VERSION 5.7 ;
  NOWIREEXTENSIONATPIN ON ;
  DIVIDERCHAR "/" ;
  BUSBITCHARS "[]" ;
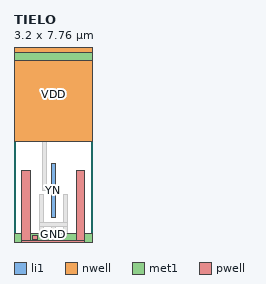
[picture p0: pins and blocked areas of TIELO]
MACRO TIELO
  CLASS CORE WELLTAP ;
  FOREIGN TIELO ;
  ORIGIN 0.000 0.000 ;
  SIZE 3.200 BY 7.760 ;
  SYMMETRY X Y ;
  SITE unitrh ;
  PIN YN
    DIRECTION OUTPUT ;
    USE SIGNAL ;
    ANTENNADIFFAREA 0.191900 ;
    PORT
      LAYER li1 ;
        RECT 1.515 1.015 1.685 3.225 ;
    END
  END YN
  PIN VDD
    DIRECTION INOUT ;
    USE POWER ;
    SHAPE ABUTMENT ;
    PORT
      LAYER nwell ;
        RECT 0.000 4.110 3.200 7.940 ;
      LAYER met1 ;
        RECT 0.000 7.410 3.200 7.760 ;
    END
  END VDD
  PIN GND
    DIRECTION INOUT ;
    USE GROUND ;
    SHAPE ABUTMENT ;
    PORT
      LAYER pwell ;
        RECT 0.320 0.055 0.660 2.900 ;
        RECT 0.775 0.095 0.945 0.265 ;
        RECT 2.540 0.055 2.880 2.900 ;
        RECT 0.320 0.000 2.880 0.055 ;
      LAYER met1 ;
        RECT 0.000 0.000 3.200 0.350 ;
    END
  END GND
  OBS
      LAYER li1 ;
        RECT 0.000 7.410 3.200 7.760 ;
        RECT 0.320 4.290 0.660 7.410 ;
        RECT 1.075 5.260 1.245 7.410 ;
        RECT 1.145 4.965 1.315 5.045 ;
        RECT 1.515 4.965 1.685 7.200 ;
        RECT 1.955 5.260 2.125 7.410 ;
        RECT 1.145 4.795 1.685 4.965 ;
        RECT 0.320 0.350 0.660 2.900 ;
        RECT 1.145 2.095 1.315 4.795 ;
        RECT 2.540 4.290 2.880 7.410 ;
        RECT 1.035 0.795 1.205 1.925 ;
        RECT 2.005 0.795 2.175 1.925 ;
        RECT 1.035 0.625 2.175 0.795 ;
        RECT 1.035 0.350 1.205 0.625 ;
        RECT 1.515 0.350 1.685 0.625 ;
        RECT 2.005 0.350 2.175 0.625 ;
        RECT 2.540 0.350 2.880 2.900 ;
        RECT 0.000 0.000 3.200 0.350 ;
      LAYER mcon ;
        RECT 0.775 7.495 0.945 7.665 ;
        RECT 1.145 7.495 1.315 7.665 ;
        RECT 1.515 7.495 1.685 7.665 ;
        RECT 1.885 7.495 2.055 7.665 ;
        RECT 2.255 7.495 2.425 7.665 ;
        RECT 0.775 0.095 0.945 0.265 ;
        RECT 1.145 0.095 1.315 0.265 ;
        RECT 1.515 0.095 1.685 0.265 ;
        RECT 1.885 0.095 2.055 0.265 ;
        RECT 2.255 0.095 2.425 0.265 ;
  END
END TIELO
END LIBRARY

